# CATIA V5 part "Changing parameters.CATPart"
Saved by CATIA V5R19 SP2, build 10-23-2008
Part number: Changing parameters
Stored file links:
  D:\Catia fórum\Modely - Makra\Changing_Parameters\Changing parameters.CATPart

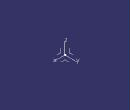
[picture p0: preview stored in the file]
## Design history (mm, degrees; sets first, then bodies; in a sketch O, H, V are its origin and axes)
Parameters
  Color = "Red"
AxisSystem1: origin (0, 0, 0), X (1, 0, 0), Y (0, 1, 0), Z (0, 0, 1)
Body1 (main body)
